VERSION 5.7 ;
  NOWIREEXTENSIONATPIN ON ;
  DIVIDERCHAR "/" ;
  BUSBITCHARS "[]" ;
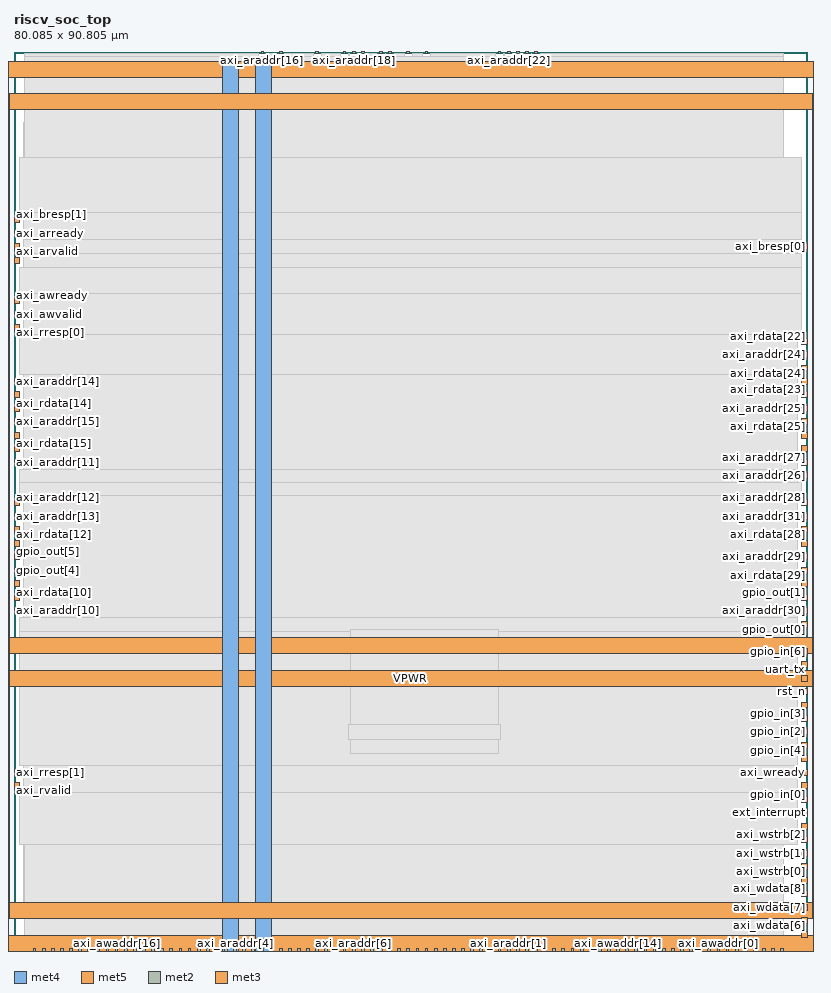
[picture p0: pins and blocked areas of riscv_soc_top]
MACRO riscv_soc_top
  CLASS BLOCK ;
  FOREIGN riscv_soc_top ;
  ORIGIN 0.000 0.000 ;
  SIZE 80.085 BY 90.805 ;
  PIN VGND
    DIRECTION INOUT ;
    USE GROUND ;
    PORT
      LAYER met4 ;
        RECT -5.380 -0.020 -3.780 89.780 ;
    END
    PORT
      LAYER met4 ;
        RECT 83.820 -0.020 85.420 89.780 ;
    END
    PORT
      LAYER met5 ;
        RECT -5.380 -0.020 85.420 1.580 ;
    END
    PORT
      LAYER met5 ;
        RECT -5.380 88.180 85.420 89.780 ;
    END
    PORT
      LAYER met4 ;
        RECT 24.340 -0.020 25.940 89.780 ;
    END
    PORT
      LAYER met5 ;
        RECT -5.380 30.030 85.420 31.630 ;
    END
  END VGND
  PIN VPWR
    DIRECTION INOUT ;
    USE POWER ;
    PORT
      LAYER met4 ;
        RECT -2.080 3.280 -0.480 86.480 ;
    END
    PORT
      LAYER met4 ;
        RECT 80.520 3.280 82.120 86.480 ;
    END
    PORT
      LAYER met5 ;
        RECT -2.080 3.280 82.120 4.880 ;
    END
    PORT
      LAYER met5 ;
        RECT -2.080 84.880 82.120 86.480 ;
    END
    PORT
      LAYER met4 ;
        RECT 21.040 -0.020 22.640 89.780 ;
    END
    PORT
      LAYER met5 ;
        RECT -5.380 26.730 85.420 28.330 ;
    END
  END VPWR
  PIN axi_araddr[0]
    DIRECTION INPUT ;
    USE SIGNAL ;
    ANTENNAGATEAREA 0.213000 ;
    PORT
      LAYER met2 ;
        RECT 47.930 0.000 48.210 0.280 ;
    END
  END axi_araddr[0]
  PIN axi_araddr[10]
    DIRECTION INPUT ;
    USE SIGNAL ;
    ANTENNAGATEAREA 0.213000 ;
    PORT
      LAYER met3 ;
        RECT 0.000 34.040 0.600 34.640 ;
    END
  END axi_araddr[10]
  PIN axi_araddr[11]
    DIRECTION INPUT ;
    USE SIGNAL ;
    ANTENNAGATEAREA 0.213000 ;
    PORT
      LAYER met3 ;
        RECT 0.000 49.000 0.600 49.600 ;
    END
  END axi_araddr[11]
  PIN axi_araddr[12]
    DIRECTION INPUT ;
    USE SIGNAL ;
    ANTENNAGATEAREA 0.213000 ;
    PORT
      LAYER met3 ;
        RECT 0.000 44.920 0.600 45.520 ;
    END
  END axi_araddr[12]
  PIN axi_araddr[13]
    DIRECTION INPUT ;
    USE SIGNAL ;
    ANTENNAGATEAREA 0.213000 ;
    PORT
      LAYER met3 ;
        RECT 0.000 43.560 0.600 44.160 ;
    END
  END axi_araddr[13]
  PIN axi_araddr[14]
    DIRECTION INPUT ;
    USE SIGNAL ;
    ANTENNAGATEAREA 0.213000 ;
    PORT
      LAYER met3 ;
        RECT 0.000 57.160 0.600 57.760 ;
    END
  END axi_araddr[14]
  PIN axi_araddr[15]
    DIRECTION INPUT ;
    USE SIGNAL ;
    ANTENNAGATEAREA 0.213000 ;
    PORT
      LAYER met3 ;
        RECT 0.000 53.080 0.600 53.680 ;
    END
  END axi_araddr[15]
  PIN axi_araddr[16]
    DIRECTION INPUT ;
    USE SIGNAL ;
    ANTENNAGATEAREA 0.213000 ;
    PORT
      LAYER met2 ;
        RECT 24.930 90.525 25.210 90.805 ;
    END
  END axi_araddr[16]
  PIN axi_araddr[17]
    DIRECTION INPUT ;
    USE SIGNAL ;
    ANTENNAGATEAREA 0.213000 ;
    PORT
      LAYER met2 ;
        RECT 30.450 90.525 30.730 90.805 ;
    END
  END axi_araddr[17]
  PIN axi_araddr[18]
    DIRECTION INPUT ;
    USE SIGNAL ;
    ANTENNAGATEAREA 0.213000 ;
    PORT
      LAYER met2 ;
        RECT 34.130 90.525 34.410 90.805 ;
    END
  END axi_araddr[18]
  PIN axi_araddr[19]
    DIRECTION INPUT ;
    USE SIGNAL ;
    ANTENNAGATEAREA 0.213000 ;
    PORT
      LAYER met2 ;
        RECT 39.650 90.525 39.930 90.805 ;
    END
  END axi_araddr[19]
  PIN axi_araddr[1]
    DIRECTION INPUT ;
    USE SIGNAL ;
    ANTENNAGATEAREA 0.213000 ;
    PORT
      LAYER met2 ;
        RECT 49.770 0.000 50.050 0.280 ;
    END
  END axi_araddr[1]
  PIN axi_araddr[20]
    DIRECTION INPUT ;
    USE SIGNAL ;
    ANTENNAGATEAREA 0.213000 ;
    PORT
      LAYER met2 ;
        RECT 48.850 90.525 49.130 90.805 ;
    END
  END axi_araddr[20]
  PIN axi_araddr[21]
    DIRECTION INPUT ;
    USE SIGNAL ;
    ANTENNAGATEAREA 0.213000 ;
    PORT
      LAYER met2 ;
        RECT 50.690 90.525 50.970 90.805 ;
    END
  END axi_araddr[21]
  PIN axi_araddr[22]
    DIRECTION INPUT ;
    USE SIGNAL ;
    ANTENNAGATEAREA 0.213000 ;
    PORT
      LAYER met2 ;
        RECT 49.770 90.525 50.050 90.805 ;
    END
  END axi_araddr[22]
  PIN axi_araddr[23]
    DIRECTION INPUT ;
    USE SIGNAL ;
    ANTENNAGATEAREA 0.213000 ;
    PORT
      LAYER met3 ;
        RECT 79.485 57.160 80.085 57.760 ;
    END
  END axi_araddr[23]
  PIN axi_araddr[24]
    DIRECTION INPUT ;
    USE SIGNAL ;
    ANTENNAGATEAREA 0.213000 ;
    PORT
      LAYER met3 ;
        RECT 79.485 59.880 80.085 60.480 ;
    END
  END axi_araddr[24]
  PIN axi_araddr[25]
    DIRECTION INPUT ;
    USE SIGNAL ;
    ANTENNAGATEAREA 0.213000 ;
    PORT
      LAYER met3 ;
        RECT 79.485 54.440 80.085 55.040 ;
    END
  END axi_araddr[25]
  PIN axi_araddr[26]
    DIRECTION INPUT ;
    USE SIGNAL ;
    ANTENNAGATEAREA 0.213000 ;
    PORT
      LAYER met3 ;
        RECT 79.485 47.640 80.085 48.240 ;
    END
  END axi_araddr[26]
  PIN axi_araddr[27]
    DIRECTION INPUT ;
    USE SIGNAL ;
    ANTENNAGATEAREA 0.213000 ;
    PORT
      LAYER met3 ;
        RECT 79.485 49.000 80.085 49.600 ;
    END
  END axi_araddr[27]
  PIN axi_araddr[28]
    DIRECTION INPUT ;
    USE SIGNAL ;
    ANTENNAGATEAREA 0.213000 ;
    PORT
      LAYER met3 ;
        RECT 79.485 44.920 80.085 45.520 ;
    END
  END axi_araddr[28]
  PIN axi_araddr[29]
    DIRECTION INPUT ;
    USE SIGNAL ;
    ANTENNAGATEAREA 0.213000 ;
    PORT
      LAYER met3 ;
        RECT 79.485 39.480 80.085 40.080 ;
    END
  END axi_araddr[29]
  PIN axi_araddr[2]
    DIRECTION INPUT ;
    USE SIGNAL ;
    ANTENNAGATEAREA 0.213000 ;
    PORT
      LAYER met2 ;
        RECT 53.450 0.000 53.730 0.280 ;
    END
  END axi_araddr[2]
  PIN axi_araddr[30]
    DIRECTION INPUT ;
    USE SIGNAL ;
    ANTENNAGATEAREA 0.213000 ;
    PORT
      LAYER met3 ;
        RECT 79.485 34.040 80.085 34.640 ;
    END
  END axi_araddr[30]
  PIN axi_araddr[31]
    DIRECTION INPUT ;
    USE SIGNAL ;
    ANTENNAGATEAREA 0.213000 ;
    PORT
      LAYER met3 ;
        RECT 79.485 43.560 80.085 44.160 ;
    END
  END axi_araddr[31]
  PIN axi_araddr[3]
    DIRECTION INPUT ;
    USE SIGNAL ;
    ANTENNAGATEAREA 0.213000 ;
    PORT
      LAYER met2 ;
        RECT 51.610 0.000 51.890 0.280 ;
    END
  END axi_araddr[3]
  PIN axi_araddr[4]
    DIRECTION INPUT ;
    USE SIGNAL ;
    ANTENNAGATEAREA 0.213000 ;
    PORT
      LAYER met2 ;
        RECT 22.170 0.000 22.450 0.280 ;
    END
  END axi_araddr[4]
  PIN axi_araddr[5]
    DIRECTION INPUT ;
    USE SIGNAL ;
    ANTENNAGATEAREA 0.213000 ;
    PORT
      LAYER met2 ;
        RECT 31.370 0.000 31.650 0.280 ;
    END
  END axi_araddr[5]
  PIN axi_araddr[6]
    DIRECTION INPUT ;
    USE SIGNAL ;
    ANTENNAGATEAREA 0.213000 ;
    PORT
      LAYER met2 ;
        RECT 34.130 0.000 34.410 0.280 ;
    END
  END axi_araddr[6]
  PIN axi_araddr[7]
    DIRECTION INPUT ;
    USE SIGNAL ;
    ANTENNAGATEAREA 0.213000 ;
    PORT
      LAYER met2 ;
        RECT 35.050 0.000 35.330 0.280 ;
    END
  END axi_araddr[7]
  PIN axi_araddr[8]
    DIRECTION INPUT ;
    USE SIGNAL ;
    ANTENNAGATEAREA 0.213000 ;
    PORT
      LAYER met2 ;
        RECT 43.330 0.000 43.610 0.280 ;
    END
  END axi_araddr[8]
  PIN axi_araddr[9]
    DIRECTION INPUT ;
    USE SIGNAL ;
    ANTENNAGATEAREA 0.213000 ;
    PORT
      LAYER met2 ;
        RECT 35.970 0.000 36.250 0.280 ;
    END
  END axi_araddr[9]
  PIN axi_arready
    DIRECTION OUTPUT ;
    USE SIGNAL ;
    ANTENNADIFFAREA 0.702900 ;
    PORT
      LAYER met3 ;
        RECT 0.000 72.120 0.600 72.720 ;
    END
  END axi_arready
  PIN axi_arvalid
    DIRECTION INPUT ;
    USE SIGNAL ;
    ANTENNAGATEAREA 0.159000 ;
    PORT
      LAYER met3 ;
        RECT 0.000 70.760 0.600 71.360 ;
    END
  END axi_arvalid
  PIN axi_awaddr[0]
    DIRECTION INPUT ;
    USE SIGNAL ;
    PORT
      LAYER met2 ;
        RECT 70.930 0.000 71.210 0.280 ;
    END
  END axi_awaddr[0]
  PIN axi_awaddr[10]
    DIRECTION INPUT ;
    USE SIGNAL ;
    PORT
      LAYER met2 ;
        RECT 13.890 0.000 14.170 0.280 ;
    END
  END axi_awaddr[10]
  PIN axi_awaddr[11]
    DIRECTION INPUT ;
    USE SIGNAL ;
    PORT
      LAYER met2 ;
        RECT 70.010 0.000 70.290 0.280 ;
    END
  END axi_awaddr[11]
  PIN axi_awaddr[12]
    DIRECTION INPUT ;
    USE SIGNAL ;
    PORT
      LAYER met2 ;
        RECT 76.450 0.000 76.730 0.280 ;
    END
  END axi_awaddr[12]
  PIN axi_awaddr[13]
    DIRECTION INPUT ;
    USE SIGNAL ;
    PORT
      LAYER met2 ;
        RECT 14.810 0.000 15.090 0.280 ;
    END
  END axi_awaddr[13]
  PIN axi_awaddr[14]
    DIRECTION INPUT ;
    USE SIGNAL ;
    PORT
      LAYER met2 ;
        RECT 60.810 0.000 61.090 0.280 ;
    END
  END axi_awaddr[14]
  PIN axi_awaddr[15]
    DIRECTION INPUT ;
    USE SIGNAL ;
    PORT
      LAYER met2 ;
        RECT 71.850 0.000 72.130 0.280 ;
    END
  END axi_awaddr[15]
  PIN axi_awaddr[16]
    DIRECTION INPUT ;
    USE SIGNAL ;
    PORT
      LAYER met2 ;
        RECT 10.210 0.000 10.490 0.280 ;
    END
  END axi_awaddr[16]
  PIN axi_awaddr[17]
    DIRECTION INPUT ;
    USE SIGNAL ;
    PORT
      LAYER met2 ;
        RECT 68.170 0.000 68.450 0.280 ;
    END
  END axi_awaddr[17]
  PIN axi_awaddr[18]
    DIRECTION INPUT ;
    USE SIGNAL ;
    PORT
      LAYER met2 ;
        RECT 19.410 0.000 19.690 0.280 ;
    END
  END axi_awaddr[18]
  PIN axi_awaddr[19]
    DIRECTION INPUT ;
    USE SIGNAL ;
    PORT
      LAYER met2 ;
        RECT 63.570 0.000 63.850 0.280 ;
    END
  END axi_awaddr[19]
  PIN axi_awaddr[1]
    DIRECTION INPUT ;
    USE SIGNAL ;
    PORT
      LAYER met2 ;
        RECT 62.650 0.000 62.930 0.280 ;
    END
  END axi_awaddr[1]
  PIN axi_awaddr[20]
    DIRECTION INPUT ;
    USE SIGNAL ;
    PORT
      LAYER met2 ;
        RECT 18.490 0.000 18.770 0.280 ;
    END
  END axi_awaddr[20]
  PIN axi_awaddr[21]
    DIRECTION INPUT ;
    USE SIGNAL ;
    PORT
      LAYER met2 ;
        RECT 67.250 0.000 67.530 0.280 ;
    END
  END axi_awaddr[21]
  PIN axi_awaddr[22]
    DIRECTION INPUT ;
    USE SIGNAL ;
    PORT
      LAYER met2 ;
        RECT 75.530 0.000 75.810 0.280 ;
    END
  END axi_awaddr[22]
  PIN axi_awaddr[23]
    DIRECTION INPUT ;
    USE SIGNAL ;
    PORT
      LAYER met2 ;
        RECT 16.650 0.000 16.930 0.280 ;
    END
  END axi_awaddr[23]
  PIN axi_awaddr[24]
    DIRECTION INPUT ;
    USE SIGNAL ;
    PORT
      LAYER met2 ;
        RECT 17.570 0.000 17.850 0.280 ;
    END
  END axi_awaddr[24]
  PIN axi_awaddr[25]
    DIRECTION INPUT ;
    USE SIGNAL ;
    PORT
      LAYER met2 ;
        RECT 21.250 0.000 21.530 0.280 ;
    END
  END axi_awaddr[25]
  PIN axi_awaddr[26]
    DIRECTION INPUT ;
    USE SIGNAL ;
    PORT
      LAYER met2 ;
        RECT 24.010 0.000 24.290 0.280 ;
    END
  END axi_awaddr[26]
  PIN axi_awaddr[27]
    DIRECTION INPUT ;
    USE SIGNAL ;
    PORT
      LAYER met2 ;
        RECT 20.330 0.000 20.610 0.280 ;
    END
  END axi_awaddr[27]
  PIN axi_awaddr[28]
    DIRECTION INPUT ;
    USE SIGNAL ;
    PORT
      LAYER met2 ;
        RECT 74.610 0.000 74.890 0.280 ;
    END
  END axi_awaddr[28]
  PIN axi_awaddr[29]
    DIRECTION INPUT ;
    USE SIGNAL ;
    PORT
      LAYER met2 ;
        RECT 3.770 0.000 4.050 0.280 ;
    END
  END axi_awaddr[29]
  PIN axi_awaddr[2]
    DIRECTION INPUT ;
    USE SIGNAL ;
    PORT
      LAYER met2 ;
        RECT 23.090 0.000 23.370 0.280 ;
    END
  END axi_awaddr[2]
  PIN axi_awaddr[30]
    DIRECTION INPUT ;
    USE SIGNAL ;
    PORT
      LAYER met2 ;
        RECT 26.770 0.000 27.050 0.280 ;
    END
  END axi_awaddr[30]
  PIN axi_awaddr[31]
    DIRECTION INPUT ;
    USE SIGNAL ;
    PORT
      LAYER met2 ;
        RECT 25.850 0.000 26.130 0.280 ;
    END
  END axi_awaddr[31]
  PIN axi_awaddr[3]
    DIRECTION INPUT ;
    USE SIGNAL ;
    PORT
      LAYER met2 ;
        RECT 28.610 0.000 28.890 0.280 ;
    END
  END axi_awaddr[3]
  PIN axi_awaddr[4]
    DIRECTION INPUT ;
    USE SIGNAL ;
    PORT
      LAYER met2 ;
        RECT 27.690 0.000 27.970 0.280 ;
    END
  END axi_awaddr[4]
  PIN axi_awaddr[5]
    DIRECTION INPUT ;
    USE SIGNAL ;
    PORT
      LAYER met2 ;
        RECT 73.690 0.000 73.970 0.280 ;
    END
  END axi_awaddr[5]
  PIN axi_awaddr[6]
    DIRECTION INPUT ;
    USE SIGNAL ;
    PORT
      LAYER met2 ;
        RECT 72.770 0.000 73.050 0.280 ;
    END
  END axi_awaddr[6]
  PIN axi_awaddr[7]
    DIRECTION INPUT ;
    USE SIGNAL ;
    PORT
      LAYER met2 ;
        RECT 29.530 0.000 29.810 0.280 ;
    END
  END axi_awaddr[7]
  PIN axi_awaddr[8]
    DIRECTION INPUT ;
    USE SIGNAL ;
    PORT
      LAYER met2 ;
        RECT 30.450 0.000 30.730 0.280 ;
    END
  END axi_awaddr[8]
  PIN axi_awaddr[9]
    DIRECTION INPUT ;
    USE SIGNAL ;
    PORT
      LAYER met2 ;
        RECT 9.290 0.000 9.570 0.280 ;
    END
  END axi_awaddr[9]
  PIN axi_awready
    DIRECTION OUTPUT ;
    USE SIGNAL ;
    ANTENNADIFFAREA 0.702900 ;
    PORT
      LAYER met3 ;
        RECT 0.000 65.320 0.600 65.920 ;
    END
  END axi_awready
  PIN axi_awvalid
    DIRECTION INPUT ;
    USE SIGNAL ;
    ANTENNAGATEAREA 0.159000 ;
    PORT
      LAYER met3 ;
        RECT 0.000 63.960 0.600 64.560 ;
    END
  END axi_awvalid
  PIN axi_bready
    DIRECTION INPUT ;
    USE SIGNAL ;
    PORT
      LAYER met2 ;
        RECT 32.290 0.000 32.570 0.280 ;
    END
  END axi_bready
  PIN axi_bresp[0]
    DIRECTION OUTPUT ;
    USE SIGNAL ;
    PORT
      LAYER met3 ;
        RECT 79.485 70.760 80.085 71.360 ;
    END
  END axi_bresp[0]
  PIN axi_bresp[1]
    DIRECTION OUTPUT ;
    USE SIGNAL ;
    PORT
      LAYER met3 ;
        RECT 0.000 73.480 0.600 74.080 ;
    END
  END axi_bresp[1]
  PIN axi_bvalid
    DIRECTION OUTPUT ;
    USE SIGNAL ;
    PORT
      LAYER met2 ;
        RECT 64.490 0.000 64.770 0.280 ;
    END
  END axi_bvalid
  PIN axi_rdata[0]
    DIRECTION OUTPUT ;
    USE SIGNAL ;
    ANTENNADIFFAREA 0.702900 ;
    PORT
      LAYER met2 ;
        RECT 50.690 0.000 50.970 0.280 ;
    END
  END axi_rdata[0]
  PIN axi_rdata[10]
    DIRECTION OUTPUT ;
    USE SIGNAL ;
    ANTENNADIFFAREA 0.702900 ;
    PORT
      LAYER met3 ;
        RECT 0.000 35.400 0.600 36.000 ;
    END
  END axi_rdata[10]
  PIN axi_rdata[11]
    DIRECTION OUTPUT ;
    USE SIGNAL ;
    ANTENNADIFFAREA 0.702900 ;
    PORT
      LAYER met2 ;
        RECT 35.050 90.525 35.330 90.805 ;
    END
  END axi_rdata[11]
  PIN axi_rdata[12]
    DIRECTION OUTPUT ;
    USE SIGNAL ;
    ANTENNADIFFAREA 0.702900 ;
    PORT
      LAYER met3 ;
        RECT 0.000 42.200 0.600 42.800 ;
    END
  END axi_rdata[12]
  PIN axi_rdata[13]
    DIRECTION OUTPUT ;
    USE SIGNAL ;
    ANTENNADIFFAREA 0.702900 ;
    PORT
      LAYER met3 ;
        RECT 0.000 40.840 0.600 41.440 ;
    END
  END axi_rdata[13]
  PIN axi_rdata[14]
    DIRECTION OUTPUT ;
    USE SIGNAL ;
    ANTENNADIFFAREA 0.702900 ;
    PORT
      LAYER met3 ;
        RECT 0.000 54.440 0.600 55.040 ;
    END
  END axi_rdata[14]
  PIN axi_rdata[15]
    DIRECTION OUTPUT ;
    USE SIGNAL ;
    ANTENNADIFFAREA 0.702900 ;
    PORT
      LAYER met3 ;
        RECT 0.000 50.360 0.600 50.960 ;
    END
  END axi_rdata[15]
  PIN axi_rdata[16]
    DIRECTION OUTPUT ;
    USE SIGNAL ;
    ANTENNADIFFAREA 0.702900 ;
    PORT
      LAYER met2 ;
        RECT 26.770 90.525 27.050 90.805 ;
    END
  END axi_rdata[16]
  PIN axi_rdata[17]
    DIRECTION OUTPUT ;
    USE SIGNAL ;
    ANTENNADIFFAREA 0.702900 ;
    PORT
      LAYER met2 ;
        RECT 33.210 90.525 33.490 90.805 ;
    END
  END axi_rdata[17]
  PIN axi_rdata[18]
    DIRECTION OUTPUT ;
    USE SIGNAL ;
    ANTENNADIFFAREA 0.702900 ;
    PORT
      LAYER met2 ;
        RECT 36.890 90.525 37.170 90.805 ;
    END
  END axi_rdata[18]
  PIN axi_rdata[19]
    DIRECTION OUTPUT ;
    USE SIGNAL ;
    ANTENNADIFFAREA 0.702900 ;
    PORT
      LAYER met2 ;
        RECT 41.490 90.525 41.770 90.805 ;
    END
  END axi_rdata[19]
  PIN axi_rdata[1]
    DIRECTION OUTPUT ;
    USE SIGNAL ;
    ANTENNADIFFAREA 0.702900 ;
    PORT
      LAYER met2 ;
        RECT 52.530 0.000 52.810 0.280 ;
    END
  END axi_rdata[1]
  PIN axi_rdata[20]
    DIRECTION OUTPUT ;
    USE SIGNAL ;
    ANTENNADIFFAREA 0.702900 ;
    PORT
      LAYER met2 ;
        RECT 51.610 90.525 51.890 90.805 ;
    END
  END axi_rdata[20]
  PIN axi_rdata[21]
    DIRECTION OUTPUT ;
    USE SIGNAL ;
    ANTENNADIFFAREA 0.702900 ;
    PORT
      LAYER met2 ;
        RECT 52.530 90.525 52.810 90.805 ;
    END
  END axi_rdata[21]
  PIN axi_rdata[22]
    DIRECTION OUTPUT ;
    USE SIGNAL ;
    ANTENNADIFFAREA 0.702900 ;
    PORT
      LAYER met3 ;
        RECT 79.485 61.240 80.085 61.840 ;
    END
  END axi_rdata[22]
  PIN axi_rdata[23]
    DIRECTION OUTPUT ;
    USE SIGNAL ;
    ANTENNADIFFAREA 0.702900 ;
    PORT
      LAYER met3 ;
        RECT 79.485 55.800 80.085 56.400 ;
    END
  END axi_rdata[23]
  PIN axi_rdata[24]
    DIRECTION OUTPUT ;
    USE SIGNAL ;
    ANTENNADIFFAREA 0.702900 ;
    PORT
      LAYER met3 ;
        RECT 79.485 58.520 80.085 59.120 ;
    END
  END axi_rdata[24]
  PIN axi_rdata[25]
    DIRECTION OUTPUT ;
    USE SIGNAL ;
    ANTENNADIFFAREA 0.702900 ;
    PORT
      LAYER met3 ;
        RECT 79.485 53.080 80.085 53.680 ;
    END
  END axi_rdata[25]
  PIN axi_rdata[26]
    DIRECTION OUTPUT ;
    USE SIGNAL ;
    ANTENNADIFFAREA 0.702900 ;
    PORT
      LAYER met3 ;
        RECT 79.485 51.720 80.085 52.320 ;
    END
  END axi_rdata[26]
  PIN axi_rdata[27]
    DIRECTION OUTPUT ;
    USE SIGNAL ;
    ANTENNADIFFAREA 0.702900 ;
    PORT
      LAYER met3 ;
        RECT 79.485 50.360 80.085 50.960 ;
    END
  END axi_rdata[27]
  PIN axi_rdata[28]
    DIRECTION OUTPUT ;
    USE SIGNAL ;
    ANTENNADIFFAREA 0.702900 ;
    PORT
      LAYER met3 ;
        RECT 79.485 42.200 80.085 42.800 ;
    END
  END axi_rdata[28]
  PIN axi_rdata[29]
    DIRECTION OUTPUT ;
    USE SIGNAL ;
    ANTENNADIFFAREA 0.702900 ;
    PORT
      LAYER met3 ;
        RECT 79.485 38.120 80.085 38.720 ;
    END
  END axi_rdata[29]
  PIN axi_rdata[2]
    DIRECTION OUTPUT ;
    USE SIGNAL ;
    ANTENNADIFFAREA 0.702900 ;
    PORT
      LAYER met2 ;
        RECT 56.210 0.000 56.490 0.280 ;
    END
  END axi_rdata[2]
  PIN axi_rdata[30]
    DIRECTION OUTPUT ;
    USE SIGNAL ;
    ANTENNADIFFAREA 0.702900 ;
    PORT
      LAYER met3 ;
        RECT 79.485 36.760 80.085 37.360 ;
    END
  END axi_rdata[30]
  PIN axi_rdata[31]
    DIRECTION OUTPUT ;
    USE SIGNAL ;
    ANTENNADIFFAREA 0.702900 ;
    PORT
      LAYER met3 ;
        RECT 79.485 40.840 80.085 41.440 ;
    END
  END axi_rdata[31]
  PIN axi_rdata[3]
    DIRECTION OUTPUT ;
    USE SIGNAL ;
    ANTENNADIFFAREA 0.702900 ;
    PORT
      LAYER met2 ;
        RECT 54.370 0.000 54.650 0.280 ;
    END
  END axi_rdata[3]
  PIN axi_rdata[4]
    DIRECTION OUTPUT ;
    USE SIGNAL ;
    ANTENNADIFFAREA 0.702900 ;
    PORT
      LAYER met2 ;
        RECT 24.930 0.000 25.210 0.280 ;
    END
  END axi_rdata[4]
  PIN axi_rdata[5]
    DIRECTION OUTPUT ;
    USE SIGNAL ;
    ANTENNADIFFAREA 0.702900 ;
    PORT
      LAYER met2 ;
        RECT 33.210 0.000 33.490 0.280 ;
    END
  END axi_rdata[5]
  PIN axi_rdata[6]
    DIRECTION OUTPUT ;
    USE SIGNAL ;
    ANTENNADIFFAREA 0.702900 ;
    PORT
      LAYER met2 ;
        RECT 36.890 0.000 37.170 0.280 ;
    END
  END axi_rdata[6]
  PIN axi_rdata[7]
    DIRECTION OUTPUT ;
    USE SIGNAL ;
    ANTENNADIFFAREA 0.702900 ;
    PORT
      LAYER met2 ;
        RECT 37.810 0.000 38.090 0.280 ;
    END
  END axi_rdata[7]
  PIN axi_rdata[8]
    DIRECTION OUTPUT ;
    USE SIGNAL ;
    ANTENNADIFFAREA 0.702900 ;
    PORT
      LAYER met2 ;
        RECT 45.170 0.000 45.450 0.280 ;
    END
  END axi_rdata[8]
  PIN axi_rdata[9]
    DIRECTION OUTPUT ;
    USE SIGNAL ;
    ANTENNADIFFAREA 0.702900 ;
    PORT
      LAYER met2 ;
        RECT 38.730 0.000 39.010 0.280 ;
    END
  END axi_rdata[9]
  PIN axi_rready
    DIRECTION INPUT ;
    USE SIGNAL ;
    PORT
      LAYER met2 ;
        RECT 5.610 0.000 5.890 0.280 ;
    END
  END axi_rready
  PIN axi_rresp[0]
    DIRECTION OUTPUT ;
    USE SIGNAL ;
    PORT
      LAYER met3 ;
        RECT 0.000 62.600 0.600 63.200 ;
    END
  END axi_rresp[0]
  PIN axi_rresp[1]
    DIRECTION OUTPUT ;
    USE SIGNAL ;
    PORT
      LAYER met3 ;
        RECT 0.000 17.720 0.600 18.320 ;
    END
  END axi_rresp[1]
  PIN axi_rvalid
    DIRECTION OUTPUT ;
    USE SIGNAL ;
    PORT
      LAYER met3 ;
        RECT 0.000 16.360 0.600 16.960 ;
    END
  END axi_rvalid
  PIN axi_wdata[0]
    DIRECTION INPUT ;
    USE SIGNAL ;
    PORT
      LAYER met2 ;
        RECT 8.370 0.000 8.650 0.280 ;
    END
  END axi_wdata[0]
  PIN axi_wdata[10]
    DIRECTION INPUT ;
    USE SIGNAL ;
    PORT
      LAYER met2 ;
        RECT 12.970 0.000 13.250 0.280 ;
    END
  END axi_wdata[10]
  PIN axi_wdata[11]
    DIRECTION INPUT ;
    USE SIGNAL ;
    PORT
      LAYER met2 ;
        RECT 2.850 0.000 3.130 0.280 ;
    END
  END axi_wdata[11]
  PIN axi_wdata[12]
    DIRECTION INPUT ;
    USE SIGNAL ;
    PORT
      LAYER met2 ;
        RECT 7.450 0.000 7.730 0.280 ;
    END
  END axi_wdata[12]
  PIN axi_wdata[13]
    DIRECTION INPUT ;
    USE SIGNAL ;
    PORT
      LAYER met2 ;
        RECT 44.250 0.000 44.530 0.280 ;
    END
  END axi_wdata[13]
  PIN axi_wdata[14]
    DIRECTION INPUT ;
    USE SIGNAL ;
    PORT
      LAYER met2 ;
        RECT 1.930 0.000 2.210 0.280 ;
    END
  END axi_wdata[14]
  PIN axi_wdata[15]
    DIRECTION INPUT ;
    USE SIGNAL ;
    PORT
      LAYER met2 ;
        RECT 39.650 0.000 39.930 0.280 ;
    END
  END axi_wdata[15]
  PIN axi_wdata[16]
    DIRECTION INPUT ;
    USE SIGNAL ;
    PORT
      LAYER met2 ;
        RECT 40.570 0.000 40.850 0.280 ;
    END
  END axi_wdata[16]
  PIN axi_wdata[17]
    DIRECTION INPUT ;
    USE SIGNAL ;
    PORT
      LAYER met2 ;
        RECT 41.490 0.000 41.770 0.280 ;
    END
  END axi_wdata[17]
  PIN axi_wdata[18]
    DIRECTION INPUT ;
    USE SIGNAL ;
    PORT
      LAYER met2 ;
        RECT 42.410 0.000 42.690 0.280 ;
    END
  END axi_wdata[18]
  PIN axi_wdata[19]
    DIRECTION INPUT ;
    USE SIGNAL ;
    PORT
      LAYER met2 ;
        RECT 6.530 0.000 6.810 0.280 ;
    END
  END axi_wdata[19]
  PIN axi_wdata[1]
    DIRECTION INPUT ;
    USE SIGNAL ;
    PORT
      LAYER met2 ;
        RECT 4.690 0.000 4.970 0.280 ;
    END
  END axi_wdata[1]
  PIN axi_wdata[20]
    DIRECTION INPUT ;
    USE SIGNAL ;
    PORT
      LAYER met2 ;
        RECT 12.050 0.000 12.330 0.280 ;
    END
  END axi_wdata[20]
  PIN axi_wdata[21]
    DIRECTION INPUT ;
    USE SIGNAL ;
    PORT
      LAYER met2 ;
        RECT 46.090 0.000 46.370 0.280 ;
    END
  END axi_wdata[21]
  PIN axi_wdata[22]
    DIRECTION INPUT ;
    USE SIGNAL ;
    PORT
      LAYER met2 ;
        RECT 47.010 0.000 47.290 0.280 ;
    END
  END axi_wdata[22]
  PIN axi_wdata[23]
    DIRECTION INPUT ;
    USE SIGNAL ;
    PORT
      LAYER met2 ;
        RECT 55.290 0.000 55.570 0.280 ;
    END
  END axi_wdata[23]
  PIN axi_wdata[24]
    DIRECTION INPUT ;
    USE SIGNAL ;
    PORT
      LAYER met2 ;
        RECT 48.850 0.000 49.130 0.280 ;
    END
  END axi_wdata[24]
  PIN axi_wdata[25]
    DIRECTION INPUT ;
    USE SIGNAL ;
    PORT
      LAYER met2 ;
        RECT 15.730 0.000 16.010 0.280 ;
    END
  END axi_wdata[25]
  PIN axi_wdata[26]
    DIRECTION INPUT ;
    USE SIGNAL ;
    PORT
      LAYER met2 ;
        RECT 61.730 0.000 62.010 0.280 ;
    END
  END axi_wdata[26]
  PIN axi_wdata[27]
    DIRECTION INPUT ;
    USE SIGNAL ;
    PORT
      LAYER met2 ;
        RECT 11.130 0.000 11.410 0.280 ;
    END
  END axi_wdata[27]
  PIN axi_wdata[28]
    DIRECTION INPUT ;
    USE SIGNAL ;
    PORT
      LAYER met2 ;
        RECT 66.330 0.000 66.610 0.280 ;
    END
  END axi_wdata[28]
  PIN axi_wdata[29]
    DIRECTION INPUT ;
    USE SIGNAL ;
    PORT
      LAYER met2 ;
        RECT 77.370 0.000 77.650 0.280 ;
    END
  END axi_wdata[29]
  PIN axi_wdata[2]
    DIRECTION INPUT ;
    USE SIGNAL ;
    PORT
      LAYER met2 ;
        RECT 65.410 0.000 65.690 0.280 ;
    END
  END axi_wdata[2]
  PIN axi_wdata[30]
    DIRECTION INPUT ;
    USE SIGNAL ;
    PORT
      LAYER met2 ;
        RECT 58.970 0.000 59.250 0.280 ;
    END
  END axi_wdata[30]
  PIN axi_wdata[31]
    DIRECTION INPUT ;
    USE SIGNAL ;
    PORT
      LAYER met2 ;
        RECT 57.130 0.000 57.410 0.280 ;
    END
  END axi_wdata[31]
  PIN axi_wdata[3]
    DIRECTION INPUT ;
    USE SIGNAL ;
    PORT
      LAYER met2 ;
        RECT 59.890 0.000 60.170 0.280 ;
    END
  END axi_wdata[3]
  PIN axi_wdata[4]
    DIRECTION INPUT ;
    USE SIGNAL ;
    PORT
      LAYER met2 ;
        RECT 69.090 0.000 69.370 0.280 ;
    END
  END axi_wdata[4]
  PIN axi_wdata[5]
    DIRECTION INPUT ;
    USE SIGNAL ;
    PORT
      LAYER met2 ;
        RECT 58.050 0.000 58.330 0.280 ;
    END
  END axi_wdata[5]
  PIN axi_wdata[6]
    DIRECTION INPUT ;
    USE SIGNAL ;
    PORT
      LAYER met3 ;
        RECT 79.485 2.760 80.085 3.360 ;
    END
  END axi_wdata[6]
  PIN axi_wdata[7]
    DIRECTION INPUT ;
    USE SIGNAL ;
    PORT
      LAYER met3 ;
        RECT 79.485 4.120 80.085 4.720 ;
    END
  END axi_wdata[7]
  PIN axi_wdata[8]
    DIRECTION INPUT ;
    USE SIGNAL ;
    PORT
      LAYER met3 ;
        RECT 79.485 5.480 80.085 6.080 ;
    END
  END axi_wdata[8]
  PIN axi_wdata[9]
    DIRECTION INPUT ;
    USE SIGNAL ;
    PORT
      LAYER met3 ;
        RECT 79.485 6.840 80.085 7.440 ;
    END
  END axi_wdata[9]
  PIN axi_wready
    DIRECTION OUTPUT ;
    USE SIGNAL ;
    ANTENNADIFFAREA 0.702900 ;
    PORT
      LAYER met3 ;
        RECT 79.485 17.720 80.085 18.320 ;
    END
  END axi_wready
  PIN axi_wstrb[0]
    DIRECTION INPUT ;
    USE SIGNAL ;
    PORT
      LAYER met3 ;
        RECT 79.485 8.200 80.085 8.800 ;
    END
  END axi_wstrb[0]
  PIN axi_wstrb[1]
    DIRECTION INPUT ;
    USE SIGNAL ;
    PORT
      LAYER met3 ;
        RECT 79.485 9.560 80.085 10.160 ;
    END
  END axi_wstrb[1]
  PIN axi_wstrb[2]
    DIRECTION INPUT ;
    USE SIGNAL ;
    PORT
      LAYER met3 ;
        RECT 79.485 10.920 80.085 11.520 ;
    END
  END axi_wstrb[2]
  PIN axi_wstrb[3]
    DIRECTION INPUT ;
    USE SIGNAL ;
    PORT
      LAYER met3 ;
        RECT 79.485 12.280 80.085 12.880 ;
    END
  END axi_wstrb[3]
  PIN axi_wvalid
    DIRECTION INPUT ;
    USE SIGNAL ;
    ANTENNAGATEAREA 0.159000 ;
    PORT
      LAYER met3 ;
        RECT 79.485 16.360 80.085 16.960 ;
    END
  END axi_wvalid
  PIN clk
    DIRECTION INPUT ;
    USE SIGNAL ;
    ANTENNAGATEAREA 0.852000 ;
    PORT
      LAYER met3 ;
        RECT 0.000 69.400 0.600 70.000 ;
    END
  END clk
  PIN ext_interrupt
    DIRECTION INPUT ;
    USE SIGNAL ;
    PORT
      LAYER met3 ;
        RECT 79.485 13.640 80.085 14.240 ;
    END
  END ext_interrupt
  PIN gpio_in[0]
    DIRECTION INPUT ;
    USE SIGNAL ;
    PORT
      LAYER met3 ;
        RECT 79.485 15.000 80.085 15.600 ;
    END
  END gpio_in[0]
  PIN gpio_in[1]
    DIRECTION INPUT ;
    USE SIGNAL ;
    PORT
      LAYER met3 ;
        RECT 79.485 19.080 80.085 19.680 ;
    END
  END gpio_in[1]
  PIN gpio_in[2]
    DIRECTION INPUT ;
    USE SIGNAL ;
    PORT
      LAYER met3 ;
        RECT 79.485 21.800 80.085 22.400 ;
    END
  END gpio_in[2]
  PIN gpio_in[3]
    DIRECTION INPUT ;
    USE SIGNAL ;
    PORT
      LAYER met3 ;
        RECT 79.485 23.160 80.085 23.760 ;
    END
  END gpio_in[3]
  PIN gpio_in[4]
    DIRECTION INPUT ;
    USE SIGNAL ;
    PORT
      LAYER met3 ;
        RECT 79.485 20.440 80.085 21.040 ;
    END
  END gpio_in[4]
  PIN gpio_in[5]
    DIRECTION INPUT ;
    USE SIGNAL ;
    PORT
      LAYER met3 ;
        RECT 79.485 24.520 80.085 25.120 ;
    END
  END gpio_in[5]
  PIN gpio_in[6]
    DIRECTION INPUT ;
    USE SIGNAL ;
    PORT
      LAYER met3 ;
        RECT 79.485 29.960 80.085 30.560 ;
    END
  END gpio_in[6]
  PIN gpio_in[7]
    DIRECTION INPUT ;
    USE SIGNAL ;
    PORT
      LAYER met3 ;
        RECT 79.485 1.400 80.085 2.000 ;
    END
  END gpio_in[7]
  PIN gpio_out[0]
    DIRECTION OUTPUT ;
    USE SIGNAL ;
    ANTENNADIFFAREA 0.702900 ;
    PORT
      LAYER met3 ;
        RECT 79.485 32.680 80.085 33.280 ;
    END
  END gpio_out[0]
  PIN gpio_out[1]
    DIRECTION OUTPUT ;
    USE SIGNAL ;
    ANTENNADIFFAREA 0.702900 ;
    PORT
      LAYER met3 ;
        RECT 79.485 35.400 80.085 36.000 ;
    END
  END gpio_out[1]
  PIN gpio_out[2]
    DIRECTION OUTPUT ;
    USE SIGNAL ;
    ANTENNADIFFAREA 0.702900 ;
    PORT
      LAYER met3 ;
        RECT 0.000 36.760 0.600 37.360 ;
    END
  END gpio_out[2]
  PIN gpio_out[3]
    DIRECTION OUTPUT ;
    USE SIGNAL ;
    ANTENNADIFFAREA 0.702900 ;
    PORT
      LAYER met2 ;
        RECT 37.810 90.525 38.090 90.805 ;
    END
  END gpio_out[3]
  PIN gpio_out[4]
    DIRECTION OUTPUT ;
    USE SIGNAL ;
    ANTENNADIFFAREA 0.702900 ;
    PORT
      LAYER met3 ;
        RECT 0.000 38.120 0.600 38.720 ;
    END
  END gpio_out[4]
  PIN gpio_out[5]
    DIRECTION OUTPUT ;
    USE SIGNAL ;
    ANTENNADIFFAREA 0.702900 ;
    PORT
      LAYER met3 ;
        RECT 0.000 39.480 0.600 40.080 ;
    END
  END gpio_out[5]
  PIN gpio_out[6]
    DIRECTION OUTPUT ;
    USE SIGNAL ;
    ANTENNADIFFAREA 0.702900 ;
    PORT
      LAYER met3 ;
        RECT 0.000 55.800 0.600 56.400 ;
    END
  END gpio_out[6]
  PIN gpio_out[7]
    DIRECTION OUTPUT ;
    USE SIGNAL ;
    ANTENNADIFFAREA 0.702900 ;
    PORT
      LAYER met3 ;
        RECT 0.000 51.720 0.600 52.320 ;
    END
  END gpio_out[7]
  PIN rst_n
    DIRECTION INPUT ;
    USE SIGNAL ;
    ANTENNAGATEAREA 0.247500 ;
    PORT
      LAYER met3 ;
        RECT 79.485 25.880 80.085 26.480 ;
    END
  END rst_n
  PIN uart_rx
    DIRECTION INPUT ;
    USE SIGNAL ;
    ANTENNAGATEAREA 0.213000 ;
    PORT
      LAYER met3 ;
        RECT 79.485 27.240 80.085 27.840 ;
    END
  END uart_rx
  PIN uart_tx
    DIRECTION OUTPUT ;
    USE SIGNAL ;
    ANTENNADIFFAREA 0.702900 ;
    PORT
      LAYER met3 ;
        RECT 79.485 28.600 80.085 29.200 ;
    END
  END uart_tx
  OBS
      LAYER nwell ;
        RECT 5.330 10.795 74.710 79.070 ;
      LAYER li1 ;
        RECT 5.520 10.795 74.520 78.965 ;
      LAYER met1 ;
        RECT 0.990 4.460 77.670 83.600 ;
      LAYER met2 ;
        RECT 1.010 90.245 24.650 90.525 ;
        RECT 25.490 90.245 26.490 90.525 ;
        RECT 27.330 90.245 30.170 90.525 ;
        RECT 31.010 90.245 32.930 90.525 ;
        RECT 33.770 90.245 33.850 90.525 ;
        RECT 34.690 90.245 34.770 90.525 ;
        RECT 35.610 90.245 36.610 90.525 ;
        RECT 37.450 90.245 37.530 90.525 ;
        RECT 38.370 90.245 39.370 90.525 ;
        RECT 40.210 90.245 41.210 90.525 ;
        RECT 42.050 90.245 48.570 90.525 ;
        RECT 49.410 90.245 49.490 90.525 ;
        RECT 50.330 90.245 50.410 90.525 ;
        RECT 51.250 90.245 51.330 90.525 ;
        RECT 52.170 90.245 52.250 90.525 ;
        RECT 53.090 90.245 77.650 90.525 ;
        RECT 1.010 0.560 77.650 90.245 ;
        RECT 1.010 0.280 1.650 0.560 ;
        RECT 2.490 0.280 2.570 0.560 ;
        RECT 3.410 0.280 3.490 0.560 ;
        RECT 4.330 0.280 4.410 0.560 ;
        RECT 5.250 0.280 5.330 0.560 ;
        RECT 6.170 0.280 6.250 0.560 ;
        RECT 7.090 0.280 7.170 0.560 ;
        RECT 8.010 0.280 8.090 0.560 ;
        RECT 8.930 0.280 9.010 0.560 ;
        RECT 9.850 0.280 9.930 0.560 ;
        RECT 10.770 0.280 10.850 0.560 ;
        RECT 11.690 0.280 11.770 0.560 ;
        RECT 12.610 0.280 12.690 0.560 ;
        RECT 13.530 0.280 13.610 0.560 ;
        RECT 14.450 0.280 14.530 0.560 ;
        RECT 15.370 0.280 15.450 0.560 ;
        RECT 16.290 0.280 16.370 0.560 ;
        RECT 17.210 0.280 17.290 0.560 ;
        RECT 18.130 0.280 18.210 0.560 ;
        RECT 19.050 0.280 19.130 0.560 ;
        RECT 19.970 0.280 20.050 0.560 ;
        RECT 20.890 0.280 20.970 0.560 ;
        RECT 21.810 0.280 21.890 0.560 ;
        RECT 22.730 0.280 22.810 0.560 ;
        RECT 23.650 0.280 23.730 0.560 ;
        RECT 24.570 0.280 24.650 0.560 ;
        RECT 25.490 0.280 25.570 0.560 ;
        RECT 26.410 0.280 26.490 0.560 ;
        RECT 27.330 0.280 27.410 0.560 ;
        RECT 28.250 0.280 28.330 0.560 ;
        RECT 29.170 0.280 29.250 0.560 ;
        RECT 30.090 0.280 30.170 0.560 ;
        RECT 31.010 0.280 31.090 0.560 ;
        RECT 31.930 0.280 32.010 0.560 ;
        RECT 32.850 0.280 32.930 0.560 ;
        RECT 33.770 0.280 33.850 0.560 ;
        RECT 34.690 0.280 34.770 0.560 ;
        RECT 35.610 0.280 35.690 0.560 ;
        RECT 36.530 0.280 36.610 0.560 ;
        RECT 37.450 0.280 37.530 0.560 ;
        RECT 38.370 0.280 38.450 0.560 ;
        RECT 39.290 0.280 39.370 0.560 ;
        RECT 40.210 0.280 40.290 0.560 ;
        RECT 41.130 0.280 41.210 0.560 ;
        RECT 42.050 0.280 42.130 0.560 ;
        RECT 42.970 0.280 43.050 0.560 ;
        RECT 43.890 0.280 43.970 0.560 ;
        RECT 44.810 0.280 44.890 0.560 ;
        RECT 45.730 0.280 45.810 0.560 ;
        RECT 46.650 0.280 46.730 0.560 ;
        RECT 47.570 0.280 47.650 0.560 ;
        RECT 48.490 0.280 48.570 0.560 ;
        RECT 49.410 0.280 49.490 0.560 ;
        RECT 50.330 0.280 50.410 0.560 ;
        RECT 51.250 0.280 51.330 0.560 ;
        RECT 52.170 0.280 52.250 0.560 ;
        RECT 53.090 0.280 53.170 0.560 ;
        RECT 54.010 0.280 54.090 0.560 ;
        RECT 54.930 0.280 55.010 0.560 ;
        RECT 55.850 0.280 55.930 0.560 ;
        RECT 56.770 0.280 56.850 0.560 ;
        RECT 57.690 0.280 57.770 0.560 ;
        RECT 58.610 0.280 58.690 0.560 ;
        RECT 59.530 0.280 59.610 0.560 ;
        RECT 60.450 0.280 60.530 0.560 ;
        RECT 61.370 0.280 61.450 0.560 ;
        RECT 62.290 0.280 62.370 0.560 ;
        RECT 63.210 0.280 63.290 0.560 ;
        RECT 64.130 0.280 64.210 0.560 ;
        RECT 65.050 0.280 65.130 0.560 ;
        RECT 65.970 0.280 66.050 0.560 ;
        RECT 66.890 0.280 66.970 0.560 ;
        RECT 67.810 0.280 67.890 0.560 ;
        RECT 68.730 0.280 68.810 0.560 ;
        RECT 69.650 0.280 69.730 0.560 ;
        RECT 70.570 0.280 70.650 0.560 ;
        RECT 71.490 0.280 71.570 0.560 ;
        RECT 72.410 0.280 72.490 0.560 ;
        RECT 73.330 0.280 73.410 0.560 ;
        RECT 74.250 0.280 74.330 0.560 ;
        RECT 75.170 0.280 75.250 0.560 ;
        RECT 76.090 0.280 76.170 0.560 ;
        RECT 77.010 0.280 77.090 0.560 ;
      LAYER met3 ;
        RECT 0.600 74.480 79.485 80.065 ;
        RECT 1.000 71.760 79.485 74.480 ;
        RECT 1.000 70.360 79.085 71.760 ;
        RECT 1.000 69.000 79.485 70.360 ;
        RECT 0.600 66.320 79.485 69.000 ;
        RECT 1.000 62.240 79.485 66.320 ;
        RECT 1.000 62.200 79.085 62.240 ;
        RECT 0.600 58.160 79.085 62.200 ;
        RECT 1.000 48.600 79.085 58.160 ;
        RECT 0.600 47.240 79.085 48.600 ;
        RECT 0.600 45.920 79.485 47.240 ;
        RECT 1.000 33.640 79.085 45.920 ;
        RECT 0.600 32.280 79.085 33.640 ;
        RECT 0.600 30.960 79.485 32.280 ;
        RECT 0.600 18.720 79.085 30.960 ;
        RECT 1.000 15.960 79.085 18.720 ;
        RECT 0.600 10.715 79.085 15.960 ;
      LAYER met4 ;
        RECT 33.910 19.895 48.890 32.465 ;
      LAYER met5 ;
        RECT 33.700 21.300 49.100 22.900 ;
  END
END riscv_soc_top
END LIBRARY

